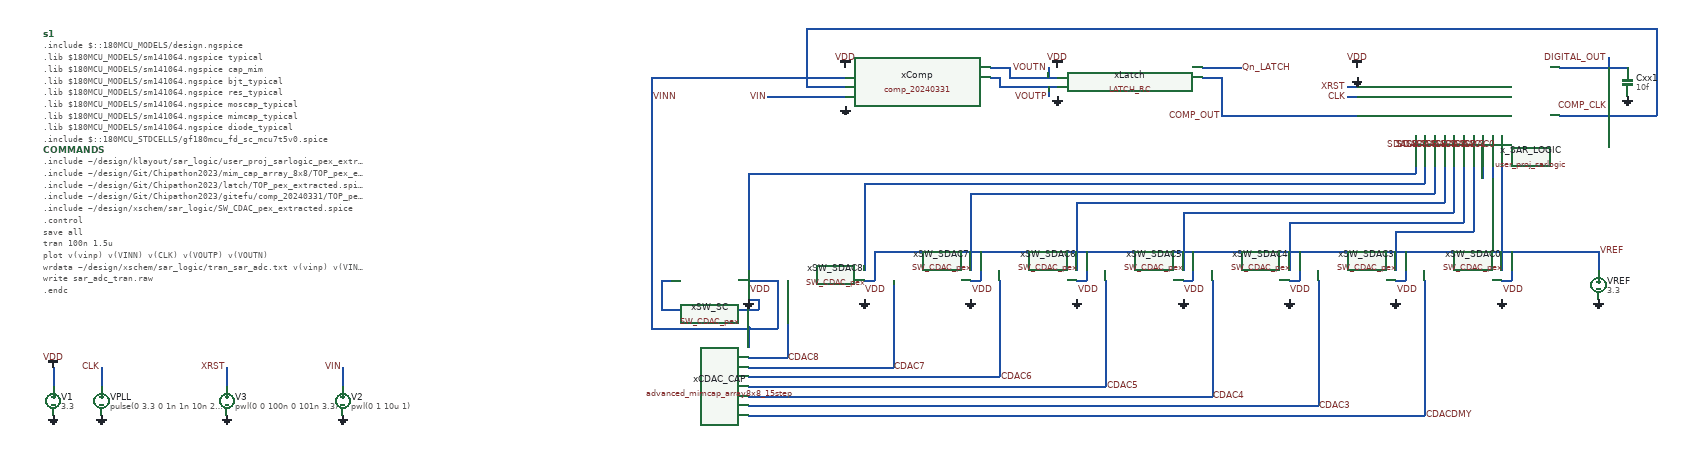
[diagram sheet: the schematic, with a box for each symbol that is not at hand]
v {xschem version=3.4.5 file_version=1.2
}
G {}
K {}
V {}
S {}
E {}
N 60 -300 60 -260 {
lab=VDD}
N 2480 -820 2760 -820 {
lab=COMP_OUT}
N 160 -300 160 -260 {
lab=CLK}
N 2740 -860 2760 -860 {
lab=CLK}
N 2740 -880 2760 -880 {
lab=XRST}
N 420 -300 420 -260 {
lab=XRST}
N 3060 -780 3060 -690 {
lab=SDAC0}
N 3050 -760 3060 -760 {
lab=SDAC0}
N 3040 -780 3040 -690 {
lab=SDAC1}
N 3030 -760 3040 -760 {
lab=SDAC1}
N 3020 -780 3020 -690 {
lab=SDAC2}
N 3010 -760 3020 -760 {
lab=SDAC2}
N 3000 -780 3000 -690 {
lab=SDAC3}
N 2990 -760 3000 -760 {
lab=SDAC3}
N 2980 -780 2980 -690 {
lab=SDAC4}
N 2970 -760 2980 -760 {
lab=SDAC4}
N 2960 -780 2960 -690 {
lab=SDAC5}
N 2950 -760 2960 -760 {
lab=SDAC5}
N 2940 -780 2940 -690 {
lab=SDAC6}
N 2930 -760 2940 -760 {
lab=SDAC6}
N 2920 -780 2920 -690 {
lab=SDAC7}
N 2910 -760 2920 -760 {
lab=SDAC7}
N 2900 -780 2900 -690 {
lab=SDAC8}
N 2890 -760 2900 -760 {
lab=SDAC8}
N 2880 -780 2880 -700 {
lab=SC}
N 2870 -760 2880 -760 {
lab=SC}
N 3180 -920 3260 -920 {
lab=DIGITAL_OUT}
N 3180 -820 3380 -820 {
lab=COMP_CLK}
N 3280 -840 3280 -820 {
lab=COMP_CLK}
N 3260 -920 3320 -920 {
lab=DIGITAL_OUT}
N 3280 -940 3280 -920 {
lab=DIGITAL_OUT}
N 2000 -920 2040 -920 {
lab=VOUTN}
N 2000 -900 2020 -900 {
lab=VOUTP}
N 1500 -320 1580 -320 {
lab=CDAC8}
N 1580 -480 1580 -320 {
lab=CDAC8}
N 1800 -480 1800 -300 {
lab=CDAC7}
N 1500 -300 1800 -300 {
lab=CDAC7}
N 1500 -280 2020 -280 {
lab=CDAC6}
N 2020 -480 2020 -280 {
lab=CDAC6}
N 1500 -260 2240 -260 {
lab=CDAC5}
N 2240 -480 2240 -260 {
lab=CDAC5}
N 1500 -240 2460 -240 {
lab=CDAC4}
N 2460 -480 2460 -240 {
lab=CDAC4}
N 1500 -220 2680 -220 {
lab=CDAC3}
N 2680 -480 2680 -220 {
lab=CDAC3}
N 1500 -200 2900 -200 {
lab=CDACDMY}
N 2900 -480 2900 -200 {
lab=CDACDMY}
N 1740 -680 2900 -680 {
lab=SDAC8}
N 1740 -680 1740 -500 {
lab=SDAC8}
N 1960 -660 1960 -500 {
lab=SDAC7}
N 1960 -660 2920 -660 {
lab=SDAC7}
N 2180 -640 2940 -640 {
lab=SDAC6}
N 2180 -640 2180 -500 {
lab=SDAC6}
N 2400 -620 2400 -500 {
lab=SDAC5}
N 2400 -620 2960 -620 {
lab=SDAC5}
N 2620 -600 2980 -600 {
lab=SDAC4}
N 2620 -600 2620 -500 {
lab=SDAC4}
N 2840 -580 2840 -500 {
lab=SDAC3}
N 3060 -690 3060 -500 {
lab=SDAC0}
N 1500 -700 2880 -700 {
lab=SC}
N 1500 -700 1500 -500 {
lab=SC}
N 1320 -480 1340 -480 {
lab=GND}
N 1320 -480 1320 -420 {
lab=GND}
N 1320 -420 1520 -420 {
lab=GND}
N 1520 -440 1520 -420 {
lab=GND}
N 1500 -440 1520 -440 {
lab=GND}
N 1500 -380 1500 -340 {
lab=VINN}
N 1300 -380 1500 -380 {
lab=VINN}
N 1300 -900 1300 -380 {
lab=VINN}
N 1300 -900 1700 -900 {
lab=VINN}
N 1500 -480 1560 -480 {
lab=VINN}
N 1560 -480 1560 -380 {
lab=VINN}
N 1500 -380 1560 -380 {
lab=VINN}
N 2840 -580 3000 -580 {
lab=SDAC3}
N 3000 -690 3000 -580 {
lab=SDAC3}
N 2980 -690 2980 -600 {
lab=SDAC4}
N 2960 -690 2960 -620 {
lab=SDAC5}
N 2940 -690 2940 -640 {
lab=SDAC6}
N 2920 -690 2920 -660 {
lab=SDAC7}
N 2900 -690 2900 -680 {
lab=SDAC8}
N 1620 -880 1700 -880 {
lab=COMP_CLK}
N 1620 -1000 1620 -880 {
lab=COMP_CLK}
N 1620 -1000 3380 -1000 {
lab=COMP_CLK}
N 3380 -1000 3380 -820 {
lab=COMP_CLK}
N 2440 -900 2480 -900 {
lab=COMP_OUT}
N 2480 -900 2480 -820 {
lab=COMP_OUT}
N 2440 -920 2520 -920 {
lab=Qn_LATCH}
N 3260 -540 3260 -500 {
lab=VREF}
N 1760 -540 3260 -540 {
lab=VREF}
N 1740 -480 1760 -480 {
lab=VREF}
N 1760 -540 1760 -480 {
lab=VREF}
N 1960 -480 1980 -480 {
lab=VREF}
N 1980 -540 1980 -480 {
lab=VREF}
N 2180 -480 2200 -480 {
lab=VREF}
N 2200 -540 2200 -480 {
lab=VREF}
N 2400 -480 2420 -480 {
lab=VREF}
N 2420 -540 2420 -480 {
lab=VREF}
N 2620 -480 2640 -480 {
lab=VREF}
N 2640 -540 2640 -480 {
lab=VREF}
N 2840 -480 2860 -480 {
lab=VREF}
N 2860 -540 2860 -480 {
lab=VREF}
N 3060 -480 3080 -480 {
lab=VREF}
N 3080 -540 3080 -480 {
lab=VREF}
N 660 -300 660 -260 {
lab=VIN}
N 1540 -860 1700 -860 {
lab=VIN}
N 2120 -920 2120 -900 {
lab=VOUTN}
N 2120 -880 2120 -860 {
lab=VOUTP}
N 2020 -900 2020 -880 {
lab=VOUTP}
N 2020 -880 2140 -880 {
lab=VOUTP}
N 2040 -920 2040 -900 {
lab=VOUTN}
N 2040 -900 2140 -900 {
lab=VOUTN}
C {devices/vsource.sym} 60 -230 0 0 {name=V1 value=3.3 savecurrent=false}
C {devices/vsource.sym} 160 -230 0 0 {name=VPLL value="pulse(0 3.3 0 1n 1n 10n 20n)" savecurrent=false}
C {devices/gnd.sym} 160 -200 0 0 {name=l2 lab=GND}
C {devices/gnd.sym} 60 -200 0 0 {name=l3 lab=GND}
C {devices/simulator_commands_shown.sym} 40 -750 0 0 {name=COMMANDS
simulator=ngspice
only_toplevel=false 
value=".include ~/design/klayout/sar_logic/user_proj_sarlogic_pex_extracted.spice
.include ~/design/Git/Chipathon2023/mim_cap_array_8x8/TOP_pex_extracted.spice
.include ~/design/Git/Chipathon2023/latch/TOP_pex_extracted.spice
.include ~/design/Git/Chipathon2023/gitefu/comp_20240331/TOP_pex_extracted.spice
.include ~/design/xschem/sar_logic/SW_CDAC_pex_extracted.spice
.control
save all
tran 100n 1.5u
plot v(vinp) v(VINN) v(CLK) v(VOUTP) v(VOUTN)
wrdata ~/design/xschem/sar_logic/tran_sar_adc.txt v(vinp) v(VINN) v(CLK) v(VOUTP) v(VOUTN)
write sar_adc_tran.raw
.endc
"}
C {devices/code_shown.sym} 40 -990 0 0 {name=s1 only_toplevel=false 
format="tcleval( @value )"
value=".include $::180MCU_MODELS/design.ngspice
.lib $180MCU_MODELS/sm141064.ngspice typical
.lib $180MCU_MODELS/sm141064.ngspice cap_mim
.lib $180MCU_MODELS/sm141064.ngspice bjt_typical
.lib $180MCU_MODELS/sm141064.ngspice res_typical
.lib $180MCU_MODELS/sm141064.ngspice moscap_typical
.lib $180MCU_MODELS/sm141064.ngspice mimcap_typical
.lib $180MCU_MODELS/sm141064.ngspice diode_typical
.include $::180MCU_STDCELLS/gf180mcu_fd_sc_mcu7t5v0.spice"}
C {design/xschem/sar_logic/user_proj_sarlogic.sym} 2970 -870 0 0 {name=x_SAR_LOGIC prefix=user_proj_sarlogic}
C {devices/lab_pin.sym} 160 -300 0 0 {name=p2 sig_type=std_logic lab=CLK}
C {devices/lab_pin.sym} 2740 -860 0 0 {name=p5 sig_type=std_logic lab=CLK}
C {devices/lab_pin.sym} 2740 -880 0 0 {name=p7 sig_type=std_logic lab=XRST}
C {devices/lab_pin.sym} 420 -300 0 0 {name=p9 sig_type=std_logic lab=XRST}
C {devices/gnd.sym} 420 -200 0 0 {name=l1 lab=GND}
C {devices/vsource.sym} 420 -230 0 0 {name=V3 value="pwl(0 0 100n 0 101n 3.3)" savecurrent=false}
C {devices/lab_pin.sym} 3050 -760 3 0 {name=p10 sig_type=std_logic lab=SDAC0}
C {devices/lab_pin.sym} 3030 -760 3 0 {name=p11 sig_type=std_logic lab=SDAC1}
C {devices/lab_pin.sym} 3010 -760 3 0 {name=p12 sig_type=std_logic lab=SDAC2}
C {devices/lab_pin.sym} 2990 -760 3 0 {name=p13 sig_type=std_logic lab=SDAC3}
C {devices/lab_pin.sym} 2970 -760 3 0 {name=p14 sig_type=std_logic lab=SDAC4}
C {devices/lab_pin.sym} 2950 -760 3 0 {name=p15 sig_type=std_logic lab=SDAC5}
C {devices/lab_pin.sym} 2930 -760 3 0 {name=p16 sig_type=std_logic lab=SDAC6}
C {devices/lab_pin.sym} 2910 -760 3 0 {name=p17 sig_type=std_logic lab=SDAC7}
C {devices/lab_pin.sym} 2890 -760 3 0 {name=p18 sig_type=std_logic lab=SDAC8}
C {devices/lab_pin.sym} 2870 -760 3 0 {name=p19 sig_type=std_logic lab=SC}
C {devices/lab_pin.sym} 3280 -840 0 0 {name=p20 sig_type=std_logic lab=COMP_CLK}
C {devices/lab_pin.sym} 3280 -940 0 0 {name=p21 sig_type=std_logic lab=DIGITAL_OUT}
C {design/Git/Chipathon2023/mim_cap_array_8x8/rev001/advanced_mimcap_array8x8_15step.sym} 1350 -270 0 0 {name=xCDAC_CAP prefix=CAP_ARRAY}
C {design/Git/Chipathon2023/gitefu/comp_20240331/comp_20240331.sym} 1850 -880 0 0 {name=xComp prefix=COMP}
C {design/xschem/sar_logic/SW_CDAC_pex.sym} 3060 -500 0 1 {name=xSW_SDAC0 prefix=SW_CDAC}
C {design/xschem/sar_logic/SW_CDAC_pex.sym} 2840 -500 0 1 {name=xSW_SDAC3 prefix=SW_CDAC}
C {design/xschem/sar_logic/SW_CDAC_pex.sym} 2620 -500 0 1 {name=xSW_SDAC4 prefix=SW_CDAC}
C {design/xschem/sar_logic/SW_CDAC_pex.sym} 2400 -500 0 1 {name=xSW_SDAC5 prefix=SW_CDAC}
C {design/xschem/sar_logic/SW_CDAC_pex.sym} 2180 -500 0 1 {name=xSW_SDAC6 prefix=SW_CDAC}
C {design/xschem/sar_logic/SW_CDAC_pex.sym} 1960 -500 0 1 {name=xSW_SDAC7 prefix=SW_CDAC}
C {design/xschem/sar_logic/SW_CDAC_pex.sym} 1740 -500 0 1 {name=xSW_SDAC8 prefix=SW_CDAC}
C {design/xschem/sar_logic/SW_CDAC_pex.sym} 1500 -500 0 1 {name=xSW_SC prefix=SW_CDAC}
C {devices/gnd.sym} 1500 -440 0 1 {name=l4 lab=GND}
C {devices/gnd.sym} 1740 -440 0 1 {name=l5 lab=GND}
C {devices/gnd.sym} 1960 -440 0 1 {name=l6 lab=GND}
C {devices/gnd.sym} 2180 -440 0 1 {name=l7 lab=GND}
C {devices/gnd.sym} 2400 -440 0 1 {name=l8 lab=GND}
C {devices/gnd.sym} 2620 -440 0 1 {name=l9 lab=GND}
C {devices/gnd.sym} 2840 -440 0 1 {name=l10 lab=GND}
C {devices/gnd.sym} 3060 -440 0 1 {name=l11 lab=GND}
C {devices/vdd.sym} 60 -300 0 0 {name=l12 lab=VDD}
C {devices/vdd.sym} 1700 -920 0 0 {name=l13 lab=VDD}
C {devices/vdd.sym} 2140 -920 0 0 {name=l14 lab=VDD}
C {devices/vdd.sym} 2760 -920 0 0 {name=l15 lab=VDD}
C {devices/gnd.sym} 2760 -900 0 1 {name=l16 lab=GND}
C {devices/lab_pin.sym} 1500 -460 2 0 {name=p1 sig_type=std_logic lab=VDD}
C {devices/lab_pin.sym} 1740 -460 2 0 {name=p3 sig_type=std_logic lab=VDD}
C {devices/lab_pin.sym} 1960 -460 2 0 {name=p4 sig_type=std_logic lab=VDD}
C {devices/lab_pin.sym} 2180 -460 2 0 {name=p6 sig_type=std_logic lab=VDD}
C {devices/lab_pin.sym} 2400 -460 2 0 {name=p8 sig_type=std_logic lab=VDD}
C {devices/lab_pin.sym} 2620 -460 2 0 {name=p22 sig_type=std_logic lab=VDD}
C {devices/lab_pin.sym} 2840 -460 2 0 {name=p23 sig_type=std_logic lab=VDD}
C {devices/lab_pin.sym} 3060 -460 2 0 {name=p24 sig_type=std_logic lab=VDD}
C {devices/vsource.sym} 3260 -470 0 0 {name=VREF value=3.3 savecurrent=false}
C {devices/gnd.sym} 3260 -440 0 0 {name=l17 lab=GND}
C {devices/gnd.sym} 1700 -840 0 1 {name=l18 lab=GND}
C {devices/gnd.sym} 2140 -860 0 1 {name=l19 lab=GND}
C {devices/capa.sym} 3320 -890 0 0 {name=Cxx1
m=1
value=10f
footprint=1206
device="ceramic capacitor"}
C {devices/gnd.sym} 3320 -860 0 1 {name=l21 lab=GND}
C {devices/lab_pin.sym} 660 -300 2 1 {name=p25 sig_type=std_logic lab=VIN}
C {devices/gnd.sym} 660 -200 0 0 {name=l22 lab=GND}
C {devices/vsource.sym} 660 -230 0 0 {name=V2 value="pwl(0 1 10u 1)" savecurrent=false}
C {devices/lab_pin.sym} 1540 -860 0 0 {name=p26 sig_type=std_logic lab=VIN}
C {devices/lab_pin.sym} 2120 -920 0 0 {name=p27 sig_type=std_logic lab=VOUTN}
C {devices/lab_pin.sym} 2120 -860 2 1 {name=p28 sig_type=std_logic lab=VOUTP}
C {devices/lab_pin.sym} 1580 -320 0 1 {name=p29 sig_type=std_logic lab=CDAC8}
C {devices/lab_pin.sym} 1800 -300 0 1 {name=p30 sig_type=std_logic lab=CDAC7}
C {devices/lab_pin.sym} 2020 -280 0 1 {name=p31 sig_type=std_logic lab=CDAC6}
C {devices/lab_pin.sym} 2240 -260 0 1 {name=p32 sig_type=std_logic lab=CDAC5}
C {devices/lab_pin.sym} 2460 -240 0 1 {name=p33 sig_type=std_logic lab=CDAC4}
C {devices/lab_pin.sym} 2680 -220 0 1 {name=p34 sig_type=std_logic lab=CDAC3}
C {devices/lab_pin.sym} 2900 -200 0 1 {name=p35 sig_type=std_logic lab=CDACDMY}
C {devices/lab_pin.sym} 1300 -860 0 1 {name=p36 sig_type=std_logic lab=VINN}
C {devices/lab_pin.sym} 3260 -540 2 0 {name=p37 sig_type=std_logic lab=VREF}
C {devices/lab_pin.sym} 2520 -920 2 0 {name=p38 sig_type=std_logic lab=Qn_LATCH}
C {devices/lab_pin.sym} 2480 -820 0 0 {name=p39 sig_type=std_logic lab=COMP_OUT}
C {design/Git/Chipathon2023/latch/LATCH_RC.sym} 2290 -890 0 0 {name=xLatch prefix=LATCH}
